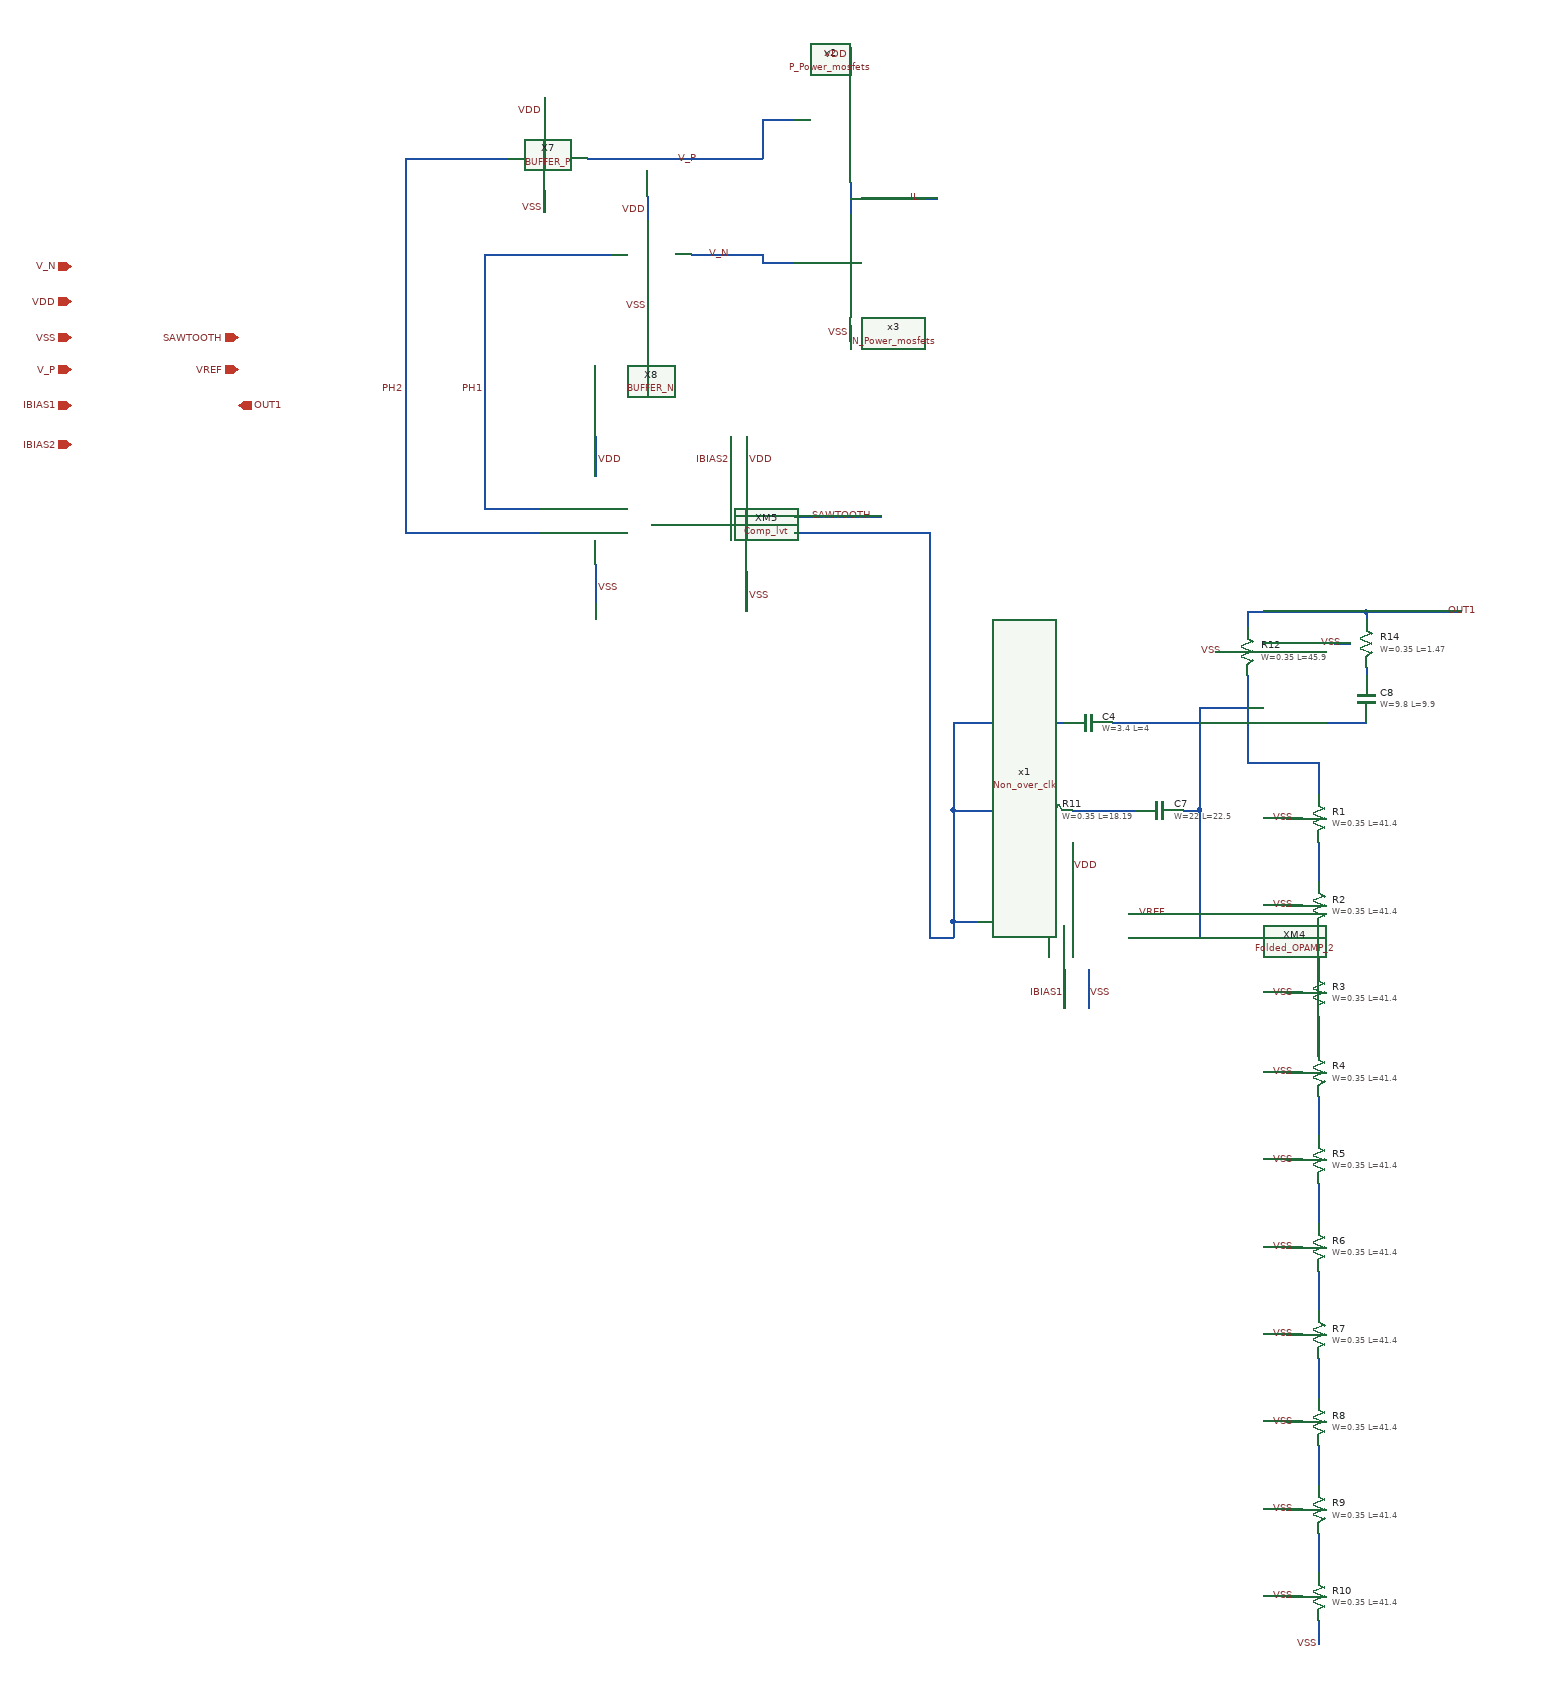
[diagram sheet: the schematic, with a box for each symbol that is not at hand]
v {xschem version=3.0.0 file_version=1.2 }
G {}
K {}
V {}
S {}
E {}
N 1690 -270 1690 -220 {
lab=VDD}
N 1710 -110 1710 -60 {
lab=VSS}
N 1680 -110 1680 -60 {
lab=IBIAS1}
N 1760 -150 1810 -150 {
lab=#net1}
N 1760 -180 1810 -180 {
lab=VREF}
N 1280 -780 1280 -730 {
lab=VDD}
N 1280 -610 1280 -560 {
lab=VSS}
N 1810 -150 1840 -150 {
lab=#net1}
N 1260 -780 1260 -730 {
lab=IBIAS2}
N 1080 -1130 1270 -1130 {
lab=V_P}
N 1910 -560 1910 -540 {
lab=OUT1}
N 1910 -480 1910 -430 {
lab=#net1}
N 1690 -310 1770 -310 {
lab=#net2}
N 1540 -310 1630 -310 {
lab=#net3}
N 1540 -310 1540 -170 {
lab=#net3}
N 1850 -310 1850 -180 {
lab=#net1}
N 1830 -310 1850 -310 {
lab=#net1}
N 1540 -420 1680 -420 {
lab=#net3}
N 1740 -420 1850 -420 {
lab=#net1}
N 1850 -380 1850 -310 {
lab=#net1}
N 1540 -170 1570 -170 {
lab=#net3}
N 1850 -180 1850 -150 {
lab=#net1}
N 1840 -150 1850 -150 {
lab=#net1}
N 1910 -560 2060 -560 {
lab=OUT1}
N 2060 -560 2060 -550 {
lab=OUT1}
N 2060 -490 2060 -480 {
lab=#net4}
N 1850 -440 1850 -380 {
lab=#net1}
N 1850 -440 1910 -440 {
lab=#net1}
N 1910 -430 1910 -400 {
lab=#net1}
N 2060 -560 2180 -560 {
lab=OUT1}
N 1340 -660 1510 -660 {
lab=#net3}
N 1540 -170 1540 -150 {
lab=#net3}
N 1090 -780 1090 -730 {
lab=VDD}
N 1090 -620 1090 -570 {
lab=VSS}
N 850 -1130 980 -1130 {
lab=PH2}
N 850 -1130 850 -690 {
lab=PH2}
N 1025 -1090 1025 -1062.5 {
lab=VSS}
N 1025 -1207.5 1025 -1172.5 {
lab=VDD}
N 1210 -1010 1270 -1010 {
lab=V_N}
N 950 -1010 1110 -1010 {
lab=PH1}
N 950 -1010 950 -920 {
lab=PH1}
N 1155 -970 1155 -932.5 {
lab=VSS}
N 1155 -1082.5 1155 -1052.5 {
lab=VDD}
N 950 -690 1010 -690 {
lab=PH1}
N 950 -920 950 -690 {
lab=PH1}
N 850 -660 1010 -660 {
lab=PH2}
N 850 -690 850 -660 {
lab=PH2}
N 1540 -420 1540 -310 {
lab=#net3}
N 1910 -420 1960 -420 {
lab=#net1}
N 1960 -420 2060 -420 {
lab=#net1}
N 1710 -110 1710 -60 {
lab=VSS}
N 1340 -680 1450 -680 {
lab=SAWTOOTH}
N 1660 -290 1660 -270 {
lab=VSS}
N 2020 -520 2040 -520 {
lab=VSS}
N 1870 -510 1890 -510 {
lab=VSS}
N 1010 -690 1020 -690 {
lab=PH1}
N 1010 -660 1020 -660 {
lab=PH2}
N 1170 -670 1210 -670 {
lab=#net5}
N 1160 -670 1170 -670 {
lab=#net5}
N 1810 -180 1820 -180 {
lab=VREF}
N 1510 -660 1510 -150 {
lab=#net3}
N 1510 -150 1540 -150 {
lab=#net3}
N 2000 -270 2000 -220 {
lab=#net6}
N 1960 -300 1980 -300 {
lab=VSS}
N 2000 -160 2000 -110 {
lab=#net7}
N 1960 -190 1980 -190 {
lab=VSS}
N 2000 -50 2000 0 {
lab=#net8}
N 1960 -80 1980 -80 {
lab=VSS}
N 2000 50 2000 100 {
lab=#net9}
N 1960 20 1980 20 {
lab=VSS}
N 2000 160 2000 210 {
lab=#net10}
N 1960 130 1980 130 {
lab=VSS}
N 2000 270 2000 320 {
lab=#net11}
N 1960 240 1980 240 {
lab=VSS}
N 2000 380 2000 430 {
lab=#net12}
N 1960 350 1980 350 {
lab=VSS}
N 2000 490 2000 540 {
lab=#net13}
N 1960 460 1980 460 {
lab=VSS}
N 2000 600 2000 650 {
lab=#net14}
N 1960 570 1980 570 {
lab=VSS}
N 1960 680 1980 680 {
lab=VSS}
N 1910 -400 1910 -370 {
lab=#net1}
N 1910 -370 2000 -370 {
lab=#net1}
N 2000 -370 2000 -330 {
lab=#net1}
N 2000 710 2000 740 {
lab=VSS}
N 1270 -1130 1300 -1130 {
lab=V_P}
N 1300 -1180 1300 -1130 {
lab=V_P}
N 1300 -1180 1340 -1180 {
lab=V_P}
N 1270 -1010 1300 -1010 {
lab=V_N}
N 1300 -1010 1300 -1000 {
lab=V_N}
N 1300 -1000 1340 -1000 {
lab=V_N}
N 1410 -1100 1410 -1060 {
lab=V_N}
N 1410 -1080 1520 -1080 {
lab=V_N}
N 1410 -920 1410 -900 {
lab=VSS}
N 1410 -1270 1410 -1240 {
lab=VDD}
C {devices/iopin.sym} 430 -950 0 0 {name=p3 lab=VDD}
C {devices/iopin.sym} 430 -905 0 0 {name=p4 lab=VSS}
C {devices/iopin.sym} 430 -820 0 0 {name=p5 lab=IBIAS1}
C {devices/ipin.sym} 640 -905 0 0 {name=p6 lab=SAWTOOTH}
C {devices/ipin.sym} 640 -865 0 0 {name=p7 lab=VREF}
C {devices/iopin.sym} 430 -770 0 0 {name=p8 lab=IBIAS2}
C {devices/iopin.sym} 430 -865 0 0 {name=p10 lab=V_P}
C {devices/iopin.sym} 640 -820 0 1 {name=p11 lab=OUT1}
C {devices/lab_wire.sym} 1690 -240 0 1 {name=l101 sig_type=std_logic lab=VDD}
C {devices/lab_wire.sym} 1710 -80 0 1 {name=l104 sig_type=std_logic lab=VSS}
C {devices/lab_wire.sym} 1680 -80 0 0 {name=l105 sig_type=std_logic lab=IBIAS1}
C {devices/lab_wire.sym} 1280 -750 0 1 {name=l106 sig_type=std_logic lab=VDD}
C {devices/lab_wire.sym} 1280 -580 0 1 {name=l107 sig_type=std_logic lab=VSS}
C {devices/lab_wire.sym} 1260 -750 0 0 {name=l110 sig_type=std_logic lab=IBIAS2}
C {devices/lab_wire.sym} 1810 -180 0 0 {name=l115 sig_type=std_logic lab=VREF}
C {devices/lab_wire.sym} 1440 -680 0 0 {name=l116 sig_type=std_logic lab=SAWTOOTH}
C {devices/lab_wire.sym} 1090 -750 0 1 {name=l121 sig_type=std_logic lab=VDD}
C {devices/lab_wire.sym} 1090 -590 0 1 {name=l122 sig_type=std_logic lab=VSS}
C {DC_DC_Converter/BUFFER/BUFFER_PMOS/BUFFER_P.sym} 960 -1080 0 0 {name=X7}
C {devices/lab_wire.sym} 1025 -1190 0 0 {name=l123 sig_type=std_logic lab=VDD}
C {devices/lab_wire.sym} 1025 -1067.5 0 0 {name=l124 sig_type=std_logic lab=VSS}
C {devices/lab_wire.sym} 1155 -945 0 0 {name=l125 sig_type=std_logic lab=VSS}
C {devices/lab_wire.sym} 1155 -1065 0 0 {name=l126 sig_type=std_logic lab=VDD}
C {devices/lab_wire.sym} 1220 -1130 0 0 {name=l127 sig_type=std_logic lab=V_P}
C {sky130_fd_pr/cap_mim_m3_1.sym} 1710 -420 3 0 {name=C4 model=cap_mim_m3_1 W=3.4 L=4 MF=1 spiceprefix=X}
C {sky130_fd_pr/cap_mim_m3_1.sym} 1800 -310 3 0 {name=C7 model=cap_mim_m3_1 W=22 L=22.5 MF=1 spiceprefix=X}
C {sky130_fd_pr/cap_mim_m3_1.sym} 2060 -450 0 0 {name=C8 model=cap_mim_m3_1 W=9.8 L=9.9 MF=1 spiceprefix=X}
C {DC_DC_Converter/Comparator/Comp_lvt.sym} 1360 -600 0 1 {name=XM5}
C {devices/lab_wire.sym} 1660 -280 3 0 {name=l132 sig_type=std_logic lab=VSS}
C {devices/lab_wire.sym} 2030 -520 0 0 {name=l133 sig_type=std_logic lab=VSS}
C {devices/lab_wire.sym} 1880 -510 0 0 {name=l134 sig_type=std_logic lab=VSS}
C {DC_DC_Converter/BUFFER/BUFFER_NMOS/BUFFER_N.sym} 1020 -930 0 0 {name=X8}
C {sky130_fd_pr/res_xhigh_po_0p35.sym} 1660 -310 3 0 {name=R11
W=0.35
L=18.19
model=res_xhigh_po_0p35
spiceprefix=X
mult=1}
C {sky130_fd_pr/res_xhigh_po_0p35.sym} 1910 -510 0 0 {name=R12
W=0.35
L=45.9
model=res_xhigh_po_0p35
spiceprefix=X
mult=1}
C {devices/lab_wire.sym} 950 -840 0 0 {name=l137 sig_type=std_logic lab=PH1}
C {devices/lab_wire.sym} 850 -840 0 0 {name=l138 sig_type=std_logic lab=PH2}
C {sky130_fd_pr/res_xhigh_po_0p35.sym} 2060 -520 0 0 {name=R14
W=0.35
L=1.47
model=res_xhigh_po_0p35
spiceprefix=X
mult=1}
C {DC_DC_Converter/Folded_OPAMP/Folded_OPAMP_2.sym} 1910 0 0 1 {name=XM4}
C {devices/lab_wire.sym} 2160 -560 0 1 {name=l7 sig_type=std_logic lab=OUT1}
C {devices/lab_wire.sym} 1260 -1010 0 0 {name=l1 sig_type=std_logic lab=V_N}
C {devices/iopin.sym} 430 -995 0 0 {name=p2 lab=V_N}
C {devices/lab_wire.sym} 1970 -300 0 0 {name=l2 sig_type=std_logic lab=VSS}
C {sky130_fd_pr/res_xhigh_po_0p35.sym} 2000 -300 0 0 {name=R1
W=0.35
L=41.4
model=res_xhigh_po_0p35
spiceprefix=X
mult=1}
C {devices/lab_wire.sym} 1970 -190 0 0 {name=l3 sig_type=std_logic lab=VSS}
C {sky130_fd_pr/res_xhigh_po_0p35.sym} 2000 -190 0 0 {name=R2
W=0.35
L=41.4
model=res_xhigh_po_0p35
spiceprefix=X
mult=1}
C {devices/lab_wire.sym} 1970 -80 0 0 {name=l5 sig_type=std_logic lab=VSS}
C {sky130_fd_pr/res_xhigh_po_0p35.sym} 2000 -80 0 0 {name=R3
W=0.35
L=41.4
model=res_xhigh_po_0p35
spiceprefix=X
mult=1}
C {devices/lab_wire.sym} 1970 20 0 0 {name=l8 sig_type=std_logic lab=VSS}
C {sky130_fd_pr/res_xhigh_po_0p35.sym} 2000 20 0 0 {name=R4
W=0.35
L=41.4
model=res_xhigh_po_0p35
spiceprefix=X
mult=1}
C {devices/lab_wire.sym} 1970 130 0 0 {name=l10 sig_type=std_logic lab=VSS}
C {sky130_fd_pr/res_xhigh_po_0p35.sym} 2000 130 0 0 {name=R5
W=0.35
L=41.4
model=res_xhigh_po_0p35
spiceprefix=X
mult=1}
C {devices/lab_wire.sym} 1970 240 0 0 {name=l12 sig_type=std_logic lab=VSS}
C {sky130_fd_pr/res_xhigh_po_0p35.sym} 2000 240 0 0 {name=R6
W=0.35
L=41.4
model=res_xhigh_po_0p35
spiceprefix=X
mult=1}
C {devices/lab_wire.sym} 1970 350 0 0 {name=l14 sig_type=std_logic lab=VSS}
C {sky130_fd_pr/res_xhigh_po_0p35.sym} 2000 350 0 0 {name=R7
W=0.35
L=41.4
model=res_xhigh_po_0p35
spiceprefix=X
mult=1}
C {devices/lab_wire.sym} 1970 460 0 0 {name=l16 sig_type=std_logic lab=VSS}
C {sky130_fd_pr/res_xhigh_po_0p35.sym} 2000 460 0 0 {name=R8
W=0.35
L=41.4
model=res_xhigh_po_0p35
spiceprefix=X
mult=1}
C {devices/lab_wire.sym} 1970 570 0 0 {name=l18 sig_type=std_logic lab=VSS}
C {sky130_fd_pr/res_xhigh_po_0p35.sym} 2000 570 0 0 {name=R9
W=0.35
L=41.4
model=res_xhigh_po_0p35
spiceprefix=X
mult=1}
C {devices/lab_wire.sym} 2000 740 0 0 {name=l19 sig_type=std_logic lab=VSS}
C {devices/lab_wire.sym} 1970 680 0 0 {name=l20 sig_type=std_logic lab=VSS}
C {sky130_fd_pr/res_xhigh_po_0p35.sym} 2000 680 0 0 {name=R10
W=0.35
L=41.4
model=res_xhigh_po_0p35
spiceprefix=X
mult=1}
C {DC_DC_Converter/Non_Overlap_Clk/Non_over_clk.sym} 1290 -410 0 1 {name=x1}
C {DC_DC_Converter/Power_Mosfet/P_Power_mosfets.sym} 1420 -1180 0 0 {name=x2}
C {DC_DC_Converter/Power_Mosfet/N_Power_mosfets.sym} 1420 -1000 0 0 {name=x3}
C {devices/lab_wire.sym} 1410 -1260 0 0 {name=l4 sig_type=std_logic lab=VDD}
C {devices/lab_wire.sym} 1410 -910 0 0 {name=l6 sig_type=std_logic lab=VSS}
C {devices/lab_wire.sym} 1500 -1080 0 0 {name=l9 sig_type=std_logic lab=IL}
